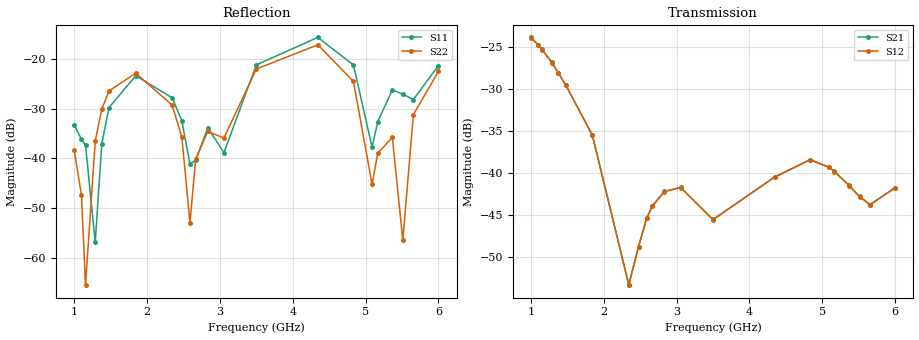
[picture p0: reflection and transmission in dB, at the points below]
!Agilent Technologies,E8364B,MY43040528,A.07.50.67
!Agilent E8364B: A.07.50.67
!Date: Sunday, March 01, 2026 16:53:18
!Correction: S11(Full 2 Port(1,2))
!S21(Full 2 Port(1,2))
!S12(Full 2 Port(1,2))
!S22(Full 2 Port(1,2))
!S2P File: Measurements: S11, S21, S12, S22:
# Hz S  dB  R 50
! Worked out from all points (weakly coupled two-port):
!   451 points, 1 GHz to 6 GHz, reference 50 ohm
!   highest |S21| = -23.90 dB at 1 GHz (marker M1); lowest = -53.3 dB at 2.344 GHz (marker M2)
!   lowest |S11| = -56.8 dB at 1.289 GHz (marker M3), VSWR 1.00, Z = 50.1 - j0.0789 ohm
!   |S11| at or under -10 dB: start of sweep to end of sweep
!   |S22| runs from -65.6 to -17.0 dB; largest |S21 - S12| = 0.00029
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1e9  -33.25 31.0  -23.90 152.9  -23.94 153.0  -38.36 -32.2
1.1e9  -36.18 34.0  -24.77 95.7  -24.81 95.8  -47.41 -48.1
1.155556e9  -37.40 31.9  -25.33 64.1  -25.36 64.2  -65.47 -57.4
1.288889e9  -56.83 -33.1  -26.88 -11.3  -26.92 -11.2  -36.52 147.2
1.377778e9  -37.19 -175.8  -28.09 -60.7  -28.13 -60.7  -30.14 123.1
1.477778e9  -29.80 154.7  -29.54 -115.3  -29.57 -115.2  -26.44 94.3
1.844444e9  -23.38 76.8  -35.50 48.9  -35.53 49.0  -22.87 -1.5
2.344444e9  -27.82 2.9  -53.26 -149.7  -53.30 -149.7  -29.29 -111.1
2.477778e9  -32.44 -16.2  -48.72 -167.0  -48.77 -166.9  -35.73 -146.7
2.588889e9  -41.11 -1.5  -45.37 144.1  -45.39 144.1  -52.95 106.6
2.666667e9  -40.42 55.5  -43.90 105.2  -43.94 105.3  -40.20 -0.5
2.833333e9  -33.85 53.8  -42.17 18.4  -42.21 18.3  -34.59 -49.2
3.055556e9  -38.85 82.2  -41.69 -99.9  -41.73 -99.9  -35.91 -35.6
3.5e9  -21.21 62.6  -45.50 38.0  -45.56 38.1  -22.04 -105.3
4.344444e9  -15.68 -41.4  -40.47 24.1  -40.50 24.2  -17.17 103.4
4.833333e9  -21.23 -125.0  -38.40 109.4  -38.44 109.5  -24.53 -14.8
5.088889e9  -37.73 -105.7  -39.28 -42.0  -39.31 -42.0  -45.20 -158.5
5.166667e9  -32.63 -54.8  -39.78 -89.0  -39.83 -89.1  -38.99 100.0
5.366667e9  -26.24 -73.0  -41.44 146.0  -41.48 146.1  -35.75 25.8
5.511111e9  -27.10 -85.3  -42.77 49.5  -42.82 49.5  -56.45 78.8
5.655556e9  -28.18 -72.5  -43.74 -53.4  -43.77 -53.4  -31.21 102.5
6e9  -21.34 -79.0  -41.73 61.6  -41.77 61.7  -22.51 4.1
